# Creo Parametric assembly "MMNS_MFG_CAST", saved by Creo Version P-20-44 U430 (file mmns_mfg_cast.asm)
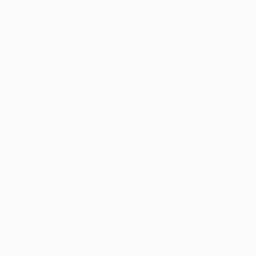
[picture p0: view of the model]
Units: millimeter Newton Second (mmNs); MM, TONNE, SECS

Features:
  1. datum plane "CAST_RIGHT"
  2. datum plane "MAIN_PARTING_PLN"
  3. datum plane "CAST_FRONT"
  4. coordinate system

Other named items: CAST_DEF_CSYS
